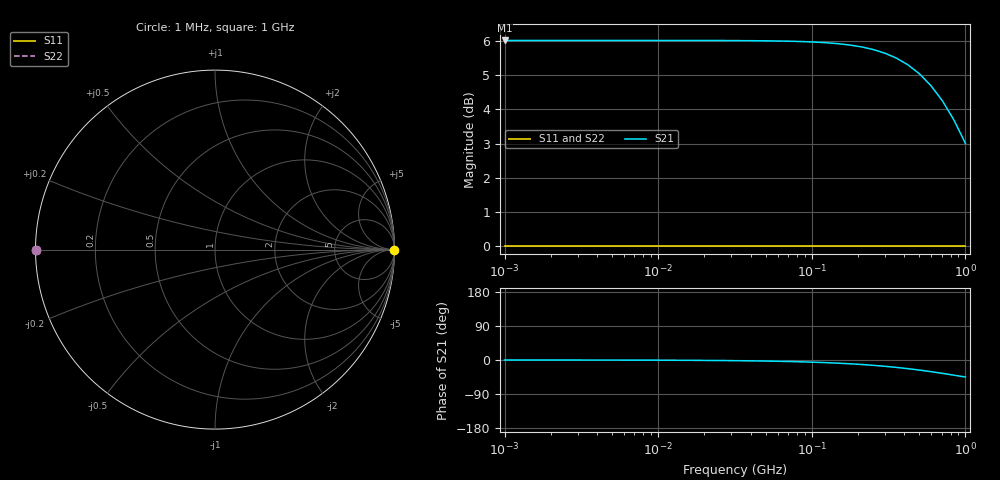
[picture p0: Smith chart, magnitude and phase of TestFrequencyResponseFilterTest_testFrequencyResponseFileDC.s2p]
! File created by SignalIntegrity v1.5.4: Signal and Power Integrity Tools
! https://github.com/Nubis-Communications/SignalIntegrity
# MHz S MA R 50.0
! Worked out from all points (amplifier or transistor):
!   41 points, 1 MHz to 1 GHz, reference 50 ohm
!   highest |S21| = 6.0 dB at 1 MHz (marker M1)
!   |S21| within 3 dB of that: start of sweep to 997.6 MHz
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1  1 0.0  2 0.0  0 0.0  1 180.0
3.349654  1 0.0  2 -0.1  0 0.0  1 180.0
11.22018  1 0.0  2 -0.6  0 0.0  1 180.0
22.38721  1 0.0  2 -1.2  0 0.0  1 180.0
37.58374  1 0.0  1.999 -2.1  0 0.0  1 180.0
53.08844  1 0.0  1.997 -3.0  0 0.0  1 180.0
63.09573  1 0.0  1.996 -3.6  0 0.0  1 180.0
89.12509  1 0.0  1.992 -5.0  0 0.0  1 180.0
105.9254  1 0.0  1.989 -6.0  0 0.0  1 180.0
125.8925  1 0.0  1.984 -7.1  0 0.0  1 180.0
149.6236  1 0.0  1.978 -8.5  0 0.0  1 180.0
177.8279  1 0.0  1.969 -10.0  0 0.0  1 180.0
211.3489  1 0.0  1.957 -11.9  0 0.0  1 180.0
251.1886  1 0.0  1.94 -14.0  0 0.0  1 180.0
298.5383  1 0.0  1.916 -16.6  0 0.0  1 180.0
354.8134  1 0.0  1.885 -19.5  0 0.0  1 180.0
421.6965  1 0.0  1.843 -22.8  0 0.0  1 180.0
501.1872  1 0.0  1.788 -26.6  0 0.0  1 180.0
595.6621  1 0.0  1.718 -30.7  0 0.0  1 180.0
707.9458  1 0.0  1.632 -35.2  0 0.0  1 180.0
841.3951  1 0.0  1.53 -40.0  0 0.0  1 180.0
1000  1 0.0  1.414 -44.9  0 0.0  1 180.0
